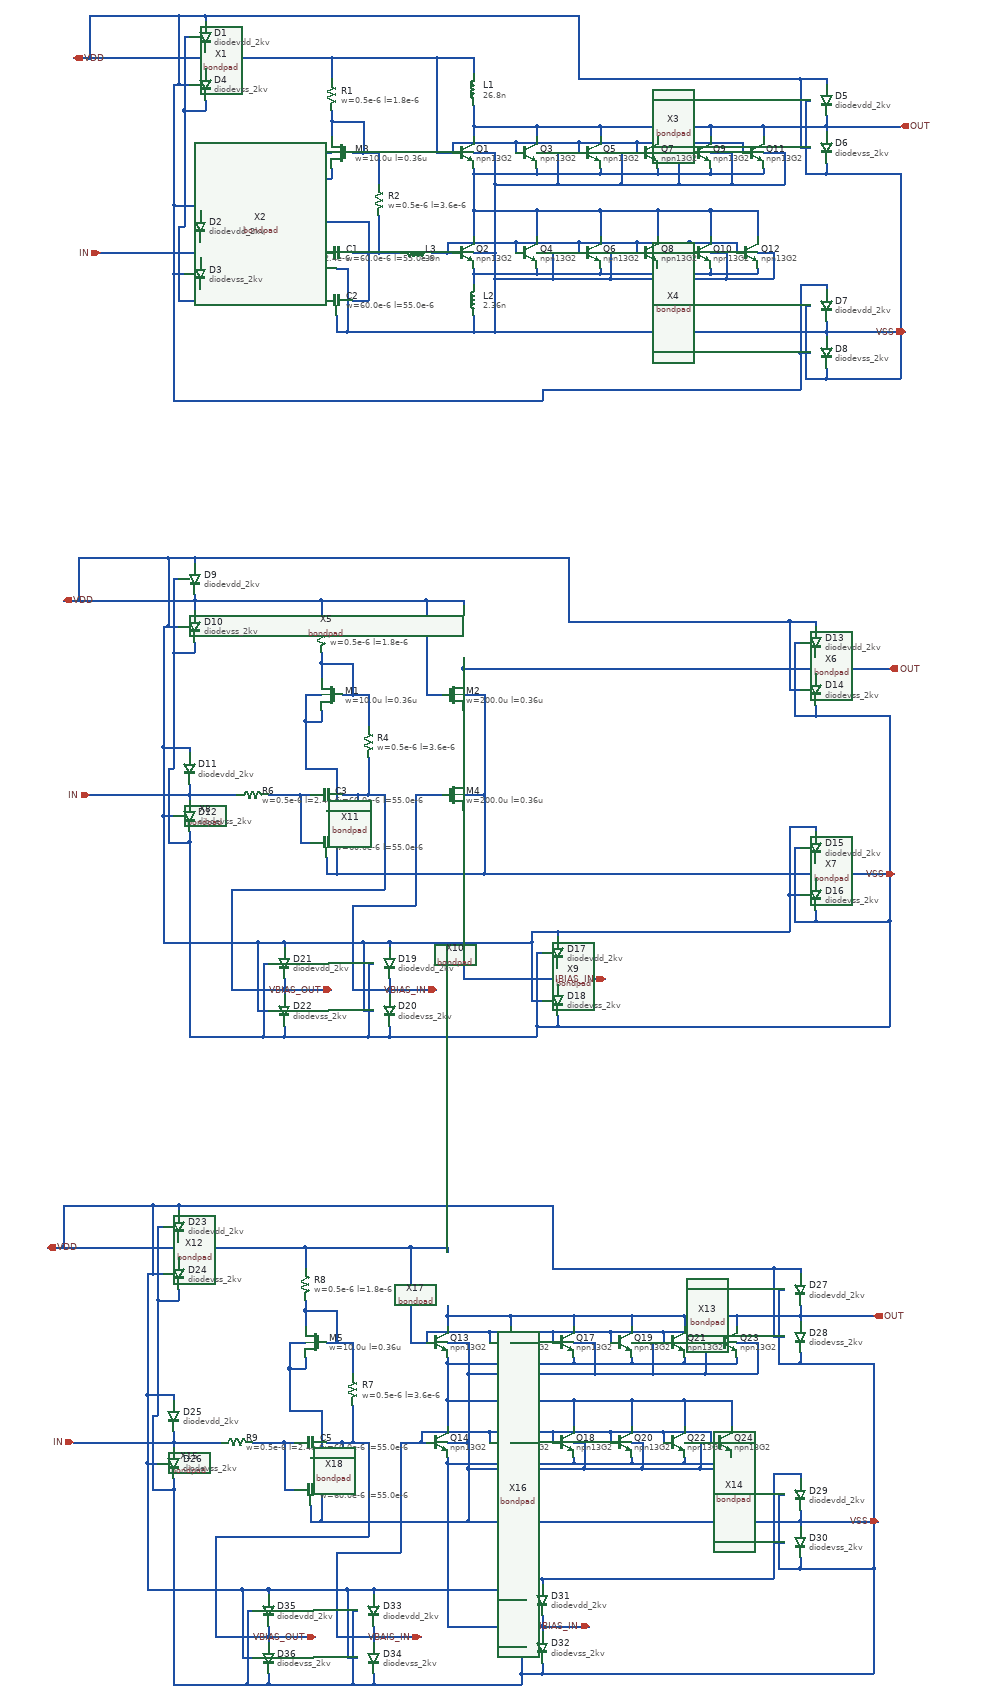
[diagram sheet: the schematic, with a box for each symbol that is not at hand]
v {xschem version=3.4.6 file_version=1.2}
G {}
K {}
V {}
S {}
E {}
N 0 -250 0 -220 {lab=#net1}
N 270 -240 270 -220 {lab=OUT}
N 270 -80 270 -30 {lab=#net2}
N 220 -0 230 0 {lab=#net3}
N -40 0 -20 0 {lab=#net4}
N 90 -70 90 0 {lab=#net5}
N 70 0 90 0 {lab=#net5}
N 70 0 70 90 {lab=#net5}
N 40 0 70 0 {lab=#net5}
N 40 90 70 90 {lab=#net5}
N -40 90 -20 90 {lab=#net4}
N -40 0 -40 90 {lab=#net4}
N -100 0 -40 0 {lab=#net4}
N 60 -190 90 -190 {lab=#net1}
N 90 -190 90 -130 {lab=#net1}
N 0 -250 60 -250 {lab=#net1}
N 0 -270 0 -250 {lab=#net1}
N 60 -250 60 -190 {lab=#net1}
N 40 -190 60 -190 {lab=#net1}
N 270 0 310 0 {lab=VSS}
N 270 -190 310 -190 {lab=VSS}
N 0 -370 0 -330 {lab=VDD}
N 310 50 310 150 {lab=VSS}
N -30 -190 0 -190 {lab=#net5}
N -30 -190 -30 -140 {lab=#net5}
N -30 -140 0 -140 {lab=#net5}
N 0 -160 0 -140 {lab=#net5}
N 200 -190 230 -190 {lab=VDD}
N 200 -370 200 -190 {lab=VDD}
N 10 30 30 30 {lab=VSS}
N 30 30 30 150 {lab=VSS}
N 10 120 10 150 {lab=VSS}
N 10 150 30 150 {lab=VSS}
N -240 -370 -240 -350 {lab=VDD}
N -240 -370 0 -370 {lab=VDD}
N -240 -380 -240 -370 {lab=VDD}
N -440 0 -250 -0 {lab=IN}
N 270 -80 390 -80 {lab=#net2}
N 390 -80 390 -30 {lab=#net2}
N 390 0 420 -0 {lab=VSS}
N 350 -20 350 -0 {lab=#net3}
N 220 -20 350 -20 {lab=#net3}
N 220 -20 220 -0 {lab=#net3}
N 0 -370 200 -370 {lab=VDD}
N 270 -150 270 -80 {lab=#net2}
N 310 -130 310 0 {lab=VSS}
N 470 -20 470 0 {lab=#net3}
N 350 -20 470 -20 {lab=#net3}
N 390 -80 510 -80 {lab=#net2}
N 510 -80 510 -30 {lab=#net2}
N 510 30 510 40 {lab=#net6}
N 510 0 530 0 {lab=VSS}
N 530 0 530 50 {lab=VSS}
N 390 30 390 40 {lab=#net6}
N 270 40 390 40 {lab=#net6}
N 270 30 270 40 {lab=#net6}
N 390 40 510 40 {lab=#net6}
N 420 50 530 50 {lab=VSS}
N 420 -0 420 50 {lab=VSS}
N 230 -210 230 -190 {lab=VDD}
N 230 -210 350 -210 {lab=VDD}
N 350 -210 350 -190 {lab=VDD}
N 350 -210 470 -210 {lab=VDD}
N 470 -210 470 -190 {lab=VDD}
N 270 -150 390 -150 {lab=#net2}
N 270 -160 270 -150 {lab=#net2}
N 390 -160 390 -150 {lab=#net2}
N 390 -150 510 -150 {lab=#net2}
N 510 -160 510 -150 {lab=#net2}
N 390 -240 390 -220 {lab=OUT}
N 270 -240 390 -240 {lab=OUT}
N 510 -240 510 -220 {lab=OUT}
N 390 -240 510 -240 {lab=OUT}
N 390 -190 430 -190 {lab=VSS}
N 430 -190 430 -130 {lab=VSS}
N 310 -130 430 -130 {lab=VSS}
N 310 -190 310 -130 {lab=VSS}
N 510 -190 550 -190 {lab=VSS}
N 550 -190 550 -130 {lab=VSS}
N 430 -130 550 -130 {lab=VSS}
N 310 50 420 50 {lab=VSS}
N 310 0 310 50 {lab=VSS}
N 620 -240 620 -220 {lab=OUT}
N 510 -240 620 -240 {lab=OUT}
N 580 -210 580 -190 {lab=VDD}
N 470 -210 580 -210 {lab=VDD}
N 620 -160 620 -150 {lab=#net2}
N 510 -150 620 -150 {lab=#net2}
N 620 -190 660 -190 {lab=VSS}
N 660 -190 660 -130 {lab=VSS}
N 550 -130 660 -130 {lab=VSS}
N 620 -80 620 -30 {lab=#net2}
N 510 -80 620 -80 {lab=#net2}
N 580 -20 580 -0 {lab=#net3}
N 470 -20 580 -20 {lab=#net3}
N 620 30 620 40 {lab=#net6}
N 510 40 620 40 {lab=#net6}
N 620 -0 640 0 {lab=VSS}
N 640 0 640 50 {lab=VSS}
N 530 50 640 50 {lab=VSS}
N -240 -450 -240 -440 {lab=VDD}
N -290 -320 -270 -320 {lab=VDD}
N -290 -450 -290 -320 {lab=VDD}
N -290 -450 -240 -450 {lab=VDD}
N -280 -410 -270 -410 {lab=#net7}
N -280 -410 -280 -270 {lab=#net7}
N -280 -270 -240 -270 {lab=#net7}
N -240 -290 -240 -270 {lab=#net7}
N -250 -0 -250 10 {lab=IN}
N -250 -90 -250 -80 {lab=VDD}
N -300 40 -280 40 {lab=VDD}
N -300 -90 -300 40 {lab=VDD}
N -300 -90 -250 -90 {lab=VDD}
N -290 -50 -280 -50 {lab=#net7}
N -290 -50 -290 90 {lab=#net7}
N -290 90 -250 90 {lab=#net7}
N -250 70 -250 90 {lab=#net7}
N 940 -240 940 -230 {lab=OUT}
N 940 -330 940 -320 {lab=VDD}
N 890 -200 910 -200 {lab=VDD}
N 890 -330 890 -200 {lab=VDD}
N 890 -330 940 -330 {lab=VDD}
N 900 -290 910 -290 {lab=VSS}
N 900 -290 900 -150 {lab=VSS}
N 900 -150 940 -150 {lab=VSS}
N 940 -170 940 -150 {lab=VSS}
N 940 150 940 160 {lab=VSS}
N 940 60 940 70 {lab=VDD}
N 890 190 910 190 {lab=VDD}
N 890 60 890 190 {lab=VDD}
N 890 60 940 60 {lab=VDD}
N 900 100 910 100 {lab=VSS}
N 900 100 900 240 {lab=VSS}
N 900 240 940 240 {lab=VSS}
N 940 220 940 240 {lab=VSS}
N 940 130 940 150 {lab=VSS}
N 310 150 940 150 {lab=VSS}
N 940 -260 940 -240 {lab=OUT}
N 820 -240 940 -240 {lab=OUT}
N -250 -20 -250 -0 {lab=IN}
N -250 -0 -160 0 {lab=IN}
N -460 -370 -240 -370 {lab=VDD}
N 720 -240 720 -220 {lab=OUT}
N 620 -240 720 -240 {lab=OUT}
N 720 -160 720 -150 {lab=#net2}
N 620 -150 720 -150 {lab=#net2}
N 680 -210 680 -190 {lab=VDD}
N 580 -210 680 -210 {lab=VDD}
N 720 -190 760 -190 {lab=VSS}
N 760 -190 760 -130 {lab=VSS}
N 660 -130 760 -130 {lab=VSS}
N 680 -20 680 -0 {lab=#net3}
N 580 -20 680 -20 {lab=#net3}
N 720 -80 720 -30 {lab=#net2}
N 620 -80 720 -80 {lab=#net2}
N 720 0 750 0 {lab=VSS}
N 750 0 750 50 {lab=VSS}
N 640 50 750 50 {lab=VSS}
N 720 30 720 40 {lab=#net6}
N 620 40 720 40 {lab=#net6}
N 720 -80 810 -80 {lab=#net2}
N 810 -80 810 -30 {lab=#net2}
N 770 -20 770 -0 {lab=#net3}
N 680 -20 770 -20 {lab=#net3}
N 810 0 840 0 {lab=VSS}
N 840 0 840 50 {lab=VSS}
N 750 50 840 50 {lab=VSS}
N 810 30 810 40 {lab=#net6}
N 720 40 810 40 {lab=#net6}
N 780 -210 780 -190 {lab=VDD}
N 680 -210 780 -210 {lab=VDD}
N 820 -240 820 -220 {lab=OUT}
N 720 -240 820 -240 {lab=OUT}
N 820 -190 860 -190 {lab=VSS}
N 860 -190 860 -130 {lab=VSS}
N 760 -130 860 -130 {lab=VSS}
N 820 -160 820 -150 {lab=#net2}
N 720 -150 820 -150 {lab=#net2}
N 200 -370 270 -370 {lab=VDD}
N 400 260 890 260 {lab=VDD}
N 1080 150 1090 150 {lab=VSS}
N 940 -240 1080 -240 {lab=OUT}
N -280 -270 -280 -50 {lab=#net7}
N 940 150 1080 150 {lab=VSS}
N 1080 -150 1080 150 {lab=VSS}
N 940 -150 1080 -150 {lab=VSS}
N -460 -450 -290 -450 {lab=VDD}
N -460 -450 -460 -370 {lab=VDD}
N -490 -370 -460 -370 {lab=VDD}
N -300 -320 -300 -90 {lab=VDD}
N -300 -320 -290 -320 {lab=VDD}
N -300 280 400 280 {lab=VDD}
N -300 40 -300 280 {lab=VDD}
N 400 260 400 280 {lab=VDD}
N 940 240 1080 240 {lab=VSS}
N 1080 150 1080 240 {lab=VSS}
N -240 -450 470 -450 {lab=VDD}
N 470 -450 470 -330 {lab=VDD}
N 470 -330 890 -330 {lab=VDD}
N 890 190 890 260 {lab=VDD}
N 270 150 310 150 {lab=VSS}
N 270 -370 270 -340 {lab=VDD}
N 270 -280 270 -240 {lab=OUT}
N 270 40 270 60 {lab=#net6}
N 270 120 270 150 {lab=VSS}
N 30 150 270 150 {lab=VSS}
N 90 0 130 0 {lab=#net5}
N 190 -0 220 -0 {lab=#net3}
N -30 -140 -30 -60 {lab=#net5}
N -30 -60 70 -60 {lab=#net5}
N 70 -60 70 0 {lab=#net5}
N -20 780 -20 810 {lab=#net1}
N 250 790 250 810 {lab=OUT}
N -60 1030 -40 1030 {lab=#net2}
N 70 960 70 1030 {lab=VBIAS_OUT}
N 50 1030 70 1030 {lab=VBIAS_OUT}
N 50 1030 50 1120 {lab=VBIAS_OUT}
N 20 1030 50 1030 {lab=VBIAS_OUT}
N 20 1120 50 1120 {lab=VBIAS_OUT}
N -60 1120 -40 1120 {lab=#net2}
N -60 1030 -60 1120 {lab=#net2}
N -120 1030 -60 1030 {lab=#net2}
N 40 840 70 840 {lab=#net1}
N 70 840 70 900 {lab=#net1}
N -20 780 40 780 {lab=#net1}
N -20 760 -20 780 {lab=#net1}
N 40 780 40 840 {lab=#net1}
N 20 840 40 840 {lab=#net1}
N 250 1030 290 1030 {lab=VSS}
N 250 840 290 840 {lab=VSS}
N -20 660 -20 700 {lab=VDD}
N -50 840 -20 840 {lab=VSS}
N -50 840 -50 890 {lab=VSS}
N -50 890 -20 890 {lab=VSS}
N -20 870 -20 890 {lab=VSS}
N 250 770 250 790 {lab=OUT}
N 180 840 210 840 {lab=VDD}
N 180 660 180 840 {lab=VDD}
N -10 1060 10 1060 {lab=VSS}
N 10 1060 10 1180 {lab=VSS}
N 10 1180 290 1180 {lab=VSS}
N -10 1150 -10 1180 {lab=VSS}
N -10 1180 10 1180 {lab=VSS}
N -260 660 -260 680 {lab=VDD}
N -260 660 -20 660 {lab=VDD}
N -260 650 -260 660 {lab=VDD}
N -460 1030 -270 1030 {lab=IN}
N -20 660 180 660 {lab=VDD}
N 250 1060 250 1380 {lab=IBIAS_IN}
N 250 870 250 1000 {lab=#net3}
N 250 790 920 790 {lab=OUT}
N 290 840 290 1030 {lab=VSS}
N 290 1030 290 1180 {lab=VSS}
N -260 580 -260 590 {lab=VDD}
N -310 710 -290 710 {lab=VDD}
N -310 580 -310 710 {lab=VDD}
N -310 580 -260 580 {lab=VDD}
N -300 620 -290 620 {lab=VSS}
N -300 620 -300 760 {lab=VSS}
N -300 760 -260 760 {lab=VSS}
N -260 740 -260 760 {lab=VSS}
N -270 1030 -270 1040 {lab=IN}
N -270 940 -270 950 {lab=VDD}
N -320 1070 -300 1070 {lab=VDD}
N -320 940 -320 1070 {lab=VDD}
N -320 940 -270 940 {lab=VDD}
N -270 1120 -270 1490 {lab=VSS}
N -310 980 -300 980 {lab=VSS}
N -310 980 -310 1120 {lab=VSS}
N -310 1120 -270 1120 {lab=VSS}
N -270 1100 -270 1120 {lab=VSS}
N 920 790 920 800 {lab=OUT}
N 920 700 920 710 {lab=VDD}
N 870 830 890 830 {lab=VDD}
N 870 700 870 830 {lab=VDD}
N 870 700 920 700 {lab=VDD}
N 880 740 890 740 {lab=VSS}
N 880 740 880 880 {lab=VSS}
N 880 880 920 880 {lab=VSS}
N 920 860 920 880 {lab=VSS}
N 920 1180 920 1190 {lab=VSS}
N 920 1090 920 1100 {lab=VDD}
N 870 1220 890 1220 {lab=VDD}
N 870 1090 870 1220 {lab=VDD}
N 870 1090 920 1090 {lab=VDD}
N 880 1130 890 1130 {lab=VSS}
N 880 1130 880 1270 {lab=VSS}
N 880 1270 920 1270 {lab=VSS}
N 920 1250 920 1270 {lab=VSS}
N 920 1160 920 1180 {lab=VSS}
N 290 1180 920 1180 {lab=VSS}
N 920 770 920 790 {lab=OUT}
N -270 1010 -270 1030 {lab=IN}
N -270 1030 -180 1030 {lab=IN}
N -480 660 -260 660 {lab=VDD}
N 180 660 250 660 {lab=VDD}
N 250 660 250 670 {lab=VDD}
N 430 1290 430 1300 {lab=VDD}
N 380 1420 400 1420 {lab=VDD}
N 380 1310 380 1420 {lab=VDD}
N 380 1290 430 1290 {lab=VDD}
N 390 1330 400 1330 {lab=VSS}
N 390 1330 390 1470 {lab=VSS}
N 390 1470 430 1470 {lab=VSS}
N 430 1450 430 1470 {lab=VSS}
N 430 1380 430 1390 {lab=IBIAS_IN}
N 430 1360 430 1380 {lab=IBIAS_IN}
N 250 1380 430 1380 {lab=IBIAS_IN}
N 110 1310 110 1320 {lab=VDD}
N 60 1440 80 1440 {lab=VDD}
N 60 1310 60 1440 {lab=VDD}
N 60 1310 110 1310 {lab=VDD}
N 70 1350 80 1350 {lab=VSS}
N 70 1350 70 1490 {lab=VSS}
N 70 1490 110 1490 {lab=VSS}
N 110 1470 110 1490 {lab=VSS}
N 110 1400 110 1410 {lab=VBIAS_IN}
N 70 1030 100 1030 {lab=VBIAS_OUT}
N 160 1030 210 1030 {lab=VBIAS_IN}
N -90 1310 -90 1320 {lab=VDD}
N -140 1440 -120 1440 {lab=VDD}
N -140 1310 -140 1440 {lab=VDD}
N -140 1310 -90 1310 {lab=VDD}
N -130 1350 -120 1350 {lab=VSS}
N -130 1350 -130 1490 {lab=VSS}
N -130 1490 -90 1490 {lab=VSS}
N -90 1470 -90 1490 {lab=VSS}
N -90 1400 -90 1410 {lab=VBIAS_OUT}
N 100 1030 100 1210 {lab=VBIAS_OUT}
N -190 1210 100 1210 {lab=VBIAS_OUT}
N -190 1210 -190 1400 {lab=VBIAS_OUT}
N -190 1400 -90 1400 {lab=VBIAS_OUT}
N -90 1380 -90 1400 {lab=VBIAS_OUT}
N -90 1400 0 1400 {lab=VBIAS_OUT}
N 160 1030 160 1240 {lab=VBIAS_IN}
N 40 1240 160 1240 {lab=VBIAS_IN}
N 40 1240 40 1400 {lab=VBIAS_IN}
N 40 1400 110 1400 {lab=VBIAS_IN}
N 110 1380 110 1400 {lab=VBIAS_IN}
N 110 1400 200 1400 {lab=VBIAS_IN}
N 1060 1180 1070 1180 {lab=VSS}
N 920 790 1060 790 {lab=OUT}
N -90 1490 70 1490 {lab=VSS}
N 110 1490 390 1490 {lab=VSS}
N 390 1470 390 1490 {lab=VSS}
N 430 1470 1060 1470 {lab=VSS}
N -270 1490 -130 1490 {lab=VSS}
N -300 760 -300 980 {lab=VSS}
N 430 1380 520 1380 {lab=IBIAS_IN}
N 1060 1270 1060 1470 {lab=VSS}
N 920 1180 1060 1180 {lab=VSS}
N 1060 880 1060 1180 {lab=VSS}
N 920 880 1060 880 {lab=VSS}
N -480 580 -310 580 {lab=VDD}
N -480 580 -480 660 {lab=VDD}
N -510 660 -480 660 {lab=VDD}
N -320 710 -320 940 {lab=VDD}
N -320 710 -310 710 {lab=VDD}
N -320 1310 -140 1310 {lab=VDD}
N -320 1070 -320 1310 {lab=VDD}
N -90 1310 60 1310 {lab=VDD}
N 110 1310 380 1310 {lab=VDD}
N 380 1290 380 1310 {lab=VDD}
N 920 1270 1060 1270 {lab=VSS}
N 1060 1180 1060 1270 {lab=VSS}
N -260 580 450 580 {lab=VDD}
N 450 580 450 700 {lab=VDD}
N 450 700 870 700 {lab=VDD}
N 430 1290 870 1290 {lab=VDD}
N 870 1220 870 1290 {lab=VDD}
N -50 890 -50 980 {lab=VSS}
N -50 980 10 980 {lab=VSS}
N 10 980 10 1060 {lab=VSS}
N -50 2010 -50 2040 {lab=#net1}
N 220 2020 220 2040 {lab=OUT}
N 220 2180 220 2230 {lab=#net2}
N 220 2300 220 2610 {lab=IBIAS_IN}
N 170 2260 180 2260 {lab=VBAIS_IN}
N -90 2260 -70 2260 {lab=#net3}
N 40 2190 40 2260 {lab=VBIAS_OUT}
N 20 2260 40 2260 {lab=VBIAS_OUT}
N 20 2260 20 2350 {lab=VBIAS_OUT}
N -10 2260 20 2260 {lab=VBIAS_OUT}
N -10 2350 20 2350 {lab=VBIAS_OUT}
N -90 2350 -70 2350 {lab=#net3}
N -90 2260 -90 2350 {lab=#net3}
N -150 2260 -90 2260 {lab=#net3}
N 10 2070 40 2070 {lab=#net1}
N 40 2070 40 2130 {lab=#net1}
N -50 2010 10 2010 {lab=#net1}
N -50 1990 -50 2010 {lab=#net1}
N 10 2010 10 2070 {lab=#net1}
N -10 2070 10 2070 {lab=#net1}
N 220 2260 260 2260 {lab=VSS}
N 220 2070 260 2070 {lab=VSS}
N -50 1890 -50 1930 {lab=VDD}
N 260 2310 260 2410 {lab=VSS}
N -80 2070 -50 2070 {lab=VSS}
N -80 2070 -80 2120 {lab=VSS}
N -80 2120 -50 2120 {lab=VSS}
N -50 2100 -50 2120 {lab=VSS}
N 220 2000 220 2020 {lab=OUT}
N 150 2070 180 2070 {lab=VDD}
N 150 1890 150 2070 {lab=VDD}
N -40 2290 -20 2290 {lab=VSS}
N -20 2290 -20 2410 {lab=VSS}
N -20 2410 260 2410 {lab=VSS}
N -40 2380 -40 2410 {lab=VSS}
N -40 2410 -20 2410 {lab=VSS}
N -290 1890 -290 1910 {lab=VDD}
N -290 1890 -50 1890 {lab=VDD}
N -290 1880 -290 1890 {lab=VDD}
N -490 2260 -300 2260 {lab=IN}
N 220 2180 340 2180 {lab=#net2}
N 340 2180 340 2230 {lab=#net2}
N 340 2260 370 2260 {lab=VSS}
N 300 2240 300 2260 {lab=VBAIS_IN}
N 170 2240 300 2240 {lab=VBAIS_IN}
N 170 2240 170 2260 {lab=VBAIS_IN}
N -50 1890 150 1890 {lab=VDD}
N 220 2110 220 2180 {lab=#net2}
N 260 2130 260 2260 {lab=VSS}
N 420 2240 420 2260 {lab=VBAIS_IN}
N 300 2240 420 2240 {lab=VBAIS_IN}
N 340 2180 460 2180 {lab=#net2}
N 460 2180 460 2230 {lab=#net2}
N 460 2290 460 2300 {lab=IBIAS_IN}
N 460 2260 480 2260 {lab=VSS}
N 480 2260 480 2310 {lab=VSS}
N 340 2290 340 2300 {lab=IBIAS_IN}
N 220 2300 340 2300 {lab=IBIAS_IN}
N 220 2290 220 2300 {lab=IBIAS_IN}
N 340 2300 460 2300 {lab=IBIAS_IN}
N 370 2310 480 2310 {lab=VSS}
N 370 2260 370 2310 {lab=VSS}
N 180 2050 180 2070 {lab=VDD}
N 180 2050 300 2050 {lab=VDD}
N 300 2050 300 2070 {lab=VDD}
N 300 2050 420 2050 {lab=VDD}
N 420 2050 420 2070 {lab=VDD}
N 220 2110 340 2110 {lab=#net2}
N 220 2100 220 2110 {lab=#net2}
N 340 2100 340 2110 {lab=#net2}
N 340 2110 460 2110 {lab=#net2}
N 460 2100 460 2110 {lab=#net2}
N 340 2020 340 2040 {lab=OUT}
N 220 2020 340 2020 {lab=OUT}
N 460 2020 460 2040 {lab=OUT}
N 340 2020 460 2020 {lab=OUT}
N 340 2070 380 2070 {lab=VSS}
N 380 2070 380 2130 {lab=VSS}
N 260 2130 380 2130 {lab=VSS}
N 260 2070 260 2130 {lab=VSS}
N 460 2070 500 2070 {lab=VSS}
N 500 2070 500 2130 {lab=VSS}
N 380 2130 500 2130 {lab=VSS}
N 260 2310 370 2310 {lab=VSS}
N 260 2260 260 2310 {lab=VSS}
N 570 2020 570 2040 {lab=OUT}
N 460 2020 570 2020 {lab=OUT}
N 530 2050 530 2070 {lab=VDD}
N 420 2050 530 2050 {lab=VDD}
N 570 2100 570 2110 {lab=#net2}
N 460 2110 570 2110 {lab=#net2}
N 570 2070 610 2070 {lab=VSS}
N 610 2070 610 2130 {lab=VSS}
N 500 2130 610 2130 {lab=VSS}
N 570 2180 570 2230 {lab=#net2}
N 460 2180 570 2180 {lab=#net2}
N 530 2240 530 2260 {lab=VBAIS_IN}
N 420 2240 530 2240 {lab=VBAIS_IN}
N 570 2290 570 2300 {lab=IBIAS_IN}
N 460 2300 570 2300 {lab=IBIAS_IN}
N 570 2260 590 2260 {lab=VSS}
N 590 2260 590 2310 {lab=VSS}
N 480 2310 590 2310 {lab=VSS}
N -290 1810 -290 1820 {lab=VDD}
N -340 1940 -320 1940 {lab=VDD}
N -340 1810 -340 1940 {lab=VDD}
N -340 1810 -290 1810 {lab=VDD}
N -330 1850 -320 1850 {lab=VSS}
N -330 1850 -330 1990 {lab=VSS}
N -330 1990 -290 1990 {lab=VSS}
N -290 1970 -290 1990 {lab=VSS}
N -300 2260 -300 2270 {lab=IN}
N -300 2170 -300 2180 {lab=VDD}
N -350 2300 -330 2300 {lab=VDD}
N -350 2170 -350 2300 {lab=VDD}
N -350 2170 -300 2170 {lab=VDD}
N -300 2350 -300 2720 {lab=VSS}
N -340 2210 -330 2210 {lab=VSS}
N -340 2210 -340 2350 {lab=VSS}
N -340 2350 -300 2350 {lab=VSS}
N -300 2330 -300 2350 {lab=VSS}
N 890 2020 890 2030 {lab=OUT}
N 890 1930 890 1940 {lab=VDD}
N 840 2060 860 2060 {lab=VDD}
N 840 1930 840 2060 {lab=VDD}
N 840 1930 890 1930 {lab=VDD}
N 850 1970 860 1970 {lab=VSS}
N 850 1970 850 2110 {lab=VSS}
N 850 2110 890 2110 {lab=VSS}
N 890 2090 890 2110 {lab=VSS}
N 890 2410 890 2420 {lab=VSS}
N 890 2320 890 2330 {lab=VDD}
N 840 2450 860 2450 {lab=VDD}
N 840 2320 840 2450 {lab=VDD}
N 840 2320 890 2320 {lab=VDD}
N 850 2360 860 2360 {lab=VSS}
N 850 2360 850 2500 {lab=VSS}
N 850 2500 890 2500 {lab=VSS}
N 890 2480 890 2500 {lab=VSS}
N 890 2390 890 2410 {lab=VSS}
N 260 2410 890 2410 {lab=VSS}
N 890 2000 890 2020 {lab=OUT}
N 770 2020 890 2020 {lab=OUT}
N -300 2240 -300 2260 {lab=IN}
N -300 2260 -210 2260 {lab=IN}
N -510 1890 -290 1890 {lab=VDD}
N 670 2020 670 2040 {lab=OUT}
N 570 2020 670 2020 {lab=OUT}
N 670 2100 670 2110 {lab=#net2}
N 570 2110 670 2110 {lab=#net2}
N 630 2050 630 2070 {lab=VDD}
N 530 2050 630 2050 {lab=VDD}
N 670 2070 710 2070 {lab=VSS}
N 710 2070 710 2130 {lab=VSS}
N 610 2130 710 2130 {lab=VSS}
N 630 2240 630 2260 {lab=VBAIS_IN}
N 530 2240 630 2240 {lab=VBAIS_IN}
N 670 2180 670 2230 {lab=#net2}
N 570 2180 670 2180 {lab=#net2}
N 670 2260 700 2260 {lab=VSS}
N 700 2260 700 2310 {lab=VSS}
N 590 2310 700 2310 {lab=VSS}
N 670 2290 670 2300 {lab=IBIAS_IN}
N 570 2300 670 2300 {lab=IBIAS_IN}
N 670 2180 760 2180 {lab=#net2}
N 760 2180 760 2230 {lab=#net2}
N 720 2240 720 2260 {lab=VBAIS_IN}
N 630 2240 720 2240 {lab=VBAIS_IN}
N 760 2260 790 2260 {lab=VSS}
N 790 2260 790 2310 {lab=VSS}
N 700 2310 790 2310 {lab=VSS}
N 760 2290 760 2300 {lab=IBIAS_IN}
N 670 2300 760 2300 {lab=IBIAS_IN}
N 730 2050 730 2070 {lab=VDD}
N 630 2050 730 2050 {lab=VDD}
N 770 2020 770 2040 {lab=OUT}
N 670 2020 770 2020 {lab=OUT}
N 770 2070 810 2070 {lab=VSS}
N 810 2070 810 2130 {lab=VSS}
N 710 2130 810 2130 {lab=VSS}
N 770 2100 770 2110 {lab=#net2}
N 670 2110 770 2110 {lab=#net2}
N 150 1890 220 1890 {lab=VDD}
N 220 1890 220 1900 {lab=VDD}
N 400 2520 400 2530 {lab=VDD}
N 350 2650 370 2650 {lab=VDD}
N 350 2540 350 2650 {lab=VDD}
N 350 2520 400 2520 {lab=VDD}
N 360 2560 370 2560 {lab=VSS}
N 360 2560 360 2700 {lab=VSS}
N 360 2700 400 2700 {lab=VSS}
N 400 2680 400 2700 {lab=VSS}
N 400 2610 400 2620 {lab=IBIAS_IN}
N 400 2590 400 2610 {lab=IBIAS_IN}
N 220 2610 400 2610 {lab=IBIAS_IN}
N 80 2540 80 2550 {lab=VDD}
N 30 2670 50 2670 {lab=VDD}
N 30 2540 30 2670 {lab=VDD}
N 30 2540 80 2540 {lab=VDD}
N 40 2580 50 2580 {lab=VSS}
N 40 2580 40 2720 {lab=VSS}
N 40 2720 80 2720 {lab=VSS}
N 80 2700 80 2720 {lab=VSS}
N 80 2630 80 2640 {lab=VBAIS_IN}
N 40 2260 70 2260 {lab=VBIAS_OUT}
N 130 2260 170 2260 {lab=VBAIS_IN}
N -120 2540 -120 2550 {lab=VDD}
N -170 2670 -150 2670 {lab=VDD}
N -170 2540 -170 2670 {lab=VDD}
N -170 2540 -120 2540 {lab=VDD}
N -160 2580 -150 2580 {lab=VSS}
N -160 2580 -160 2720 {lab=VSS}
N -160 2720 -120 2720 {lab=VSS}
N -120 2700 -120 2720 {lab=VSS}
N -120 2630 -120 2640 {lab=VBIAS_OUT}
N 70 2260 70 2440 {lab=VBIAS_OUT}
N -220 2440 70 2440 {lab=VBIAS_OUT}
N -220 2440 -220 2630 {lab=VBIAS_OUT}
N -220 2630 -120 2630 {lab=VBIAS_OUT}
N -120 2610 -120 2630 {lab=VBIAS_OUT}
N -120 2630 -30 2630 {lab=VBIAS_OUT}
N 130 2260 130 2470 {lab=VBAIS_IN}
N 10 2470 130 2470 {lab=VBAIS_IN}
N 10 2470 10 2630 {lab=VBAIS_IN}
N 10 2630 80 2630 {lab=VBAIS_IN}
N 80 2610 80 2630 {lab=VBAIS_IN}
N 80 2630 170 2630 {lab=VBAIS_IN}
N 1030 2410 1040 2410 {lab=VSS}
N 890 2020 1030 2020 {lab=OUT}
N -120 2720 40 2720 {lab=VSS}
N 80 2720 360 2720 {lab=VSS}
N 360 2700 360 2720 {lab=VSS}
N 400 2700 1030 2700 {lab=VSS}
N -300 2720 -160 2720 {lab=VSS}
N -330 1990 -330 2210 {lab=VSS}
N 400 2610 490 2610 {lab=IBIAS_IN}
N 1030 2500 1030 2700 {lab=VSS}
N 890 2410 1030 2410 {lab=VSS}
N 1030 2110 1030 2410 {lab=VSS}
N 890 2110 1030 2110 {lab=VSS}
N -510 1810 -340 1810 {lab=VDD}
N -510 1810 -510 1890 {lab=VDD}
N -540 1890 -510 1890 {lab=VDD}
N -350 1940 -350 2170 {lab=VDD}
N -350 1940 -340 1940 {lab=VDD}
N -350 2540 -170 2540 {lab=VDD}
N -350 2300 -350 2540 {lab=VDD}
N -120 2540 30 2540 {lab=VDD}
N 80 2540 350 2540 {lab=VDD}
N 350 2520 350 2540 {lab=VDD}
N 890 2500 1030 2500 {lab=VSS}
N 1030 2410 1030 2500 {lab=VSS}
N -290 1810 420 1810 {lab=VDD}
N 420 1810 420 1930 {lab=VDD}
N 420 1930 840 1930 {lab=VDD}
N 400 2520 840 2520 {lab=VDD}
N 840 2450 840 2520 {lab=VDD}
N -80 2120 -80 2200 {lab=VSS}
N -80 2200 -20 2200 {lab=VSS}
N -20 2200 -20 2290 {lab=VSS}
C {sg13g2_pr/rppd.sym} 90 -100 0 0 {name=R2
w=0.5e-6
l=3.6e-6
model=rppd
spiceprefix=X
b=0
m=1
}
C {sg13g2_pr/rppd.sym} 0 -300 0 0 {name=R1
w=0.5e-6
l=1.8e-6
model=rppd
spiceprefix=X
b=0
m=1
}
C {sg13g2_pr/rsil.sym} -130 0 3 0 {name=R3
w=0.5e-6
l=2.4e-6
model=rsil
spiceprefix=X
b=0
m=1
}
C {sg13g2_pr/cap_rfcmim.sym} 10 0 3 0 {name=C1 
model=rfcmim
w=60.0e-6
l=55.0e-6
wfeed=5.0e-6
spiceprefix=X}
C {sg13g2_pr/cap_rfcmim.sym} 10 90 3 0 {name=C2 
model=rfcmim
w=60.0e-6
l=55.0e-6
wfeed=5.0e-6
spiceprefix=X}
C {sg13g2_pr/sg13_lv_rf_nmos.sym} 20 -190 2 0 {name=M3
l=0.36u
w=10.0u
ng=5
m=1
rfmode=1
model=rfnmos
spiceprefix=X
}
C {sg13g2_pr/bondpad.sym} -400 -410 0 0 {name=X1
model=bondpad
spiceprefix=X
size=100u
shape=0
padtype=0
}
C {sg13g2_pr/bondpad.sym} 1030 -280 0 0 {name=X3
model=bondpad
spiceprefix=X
size=100u
shape=0
padtype=0
}
C {sg13g2_pr/bondpad.sym} 1040 110 0 0 {name=X4
model=bondpad
spiceprefix=X
size=100u
shape=0
padtype=0
}
C {sg13g2_pr/diodevdd_2kv.sym} -240 -410 0 0 {name=D1
model=diodevdd_2kv
m=1
spiceprefix=X
}
C {sg13g2_pr/diodevss_2kv.sym} -240 -320 0 0 {name=D4
model=diodevss_2kv
spiceprefix=X
m=1
}
C {sg13g2_pr/bondpad.sym} -380 -40 0 0 {name=X2
model=bondpad
spiceprefix=X
size=100u
shape=0
padtype=0
}
C {sg13g2_pr/npn13G2.sym} 250 -190 0 0 {name=Q1
model=npn13G2
spiceprefix=X
Nx=10
m=10}
C {sg13g2_pr/npn13G2.sym} 250 0 0 0 {name=Q2
model=npn13G2
spiceprefix=X
Nx=10
m=10}
C {sg13g2_pr/npn13G2.sym} 370 -190 0 0 {name=Q3
model=npn13G2
spiceprefix=X
Nx=10}
C {sg13g2_pr/npn13G2.sym} 370 0 0 0 {name=Q4
model=npn13G2
spiceprefix=X
Nx=10}
C {sg13g2_pr/npn13G2.sym} 490 -190 0 0 {name=Q5
model=npn13G2
spiceprefix=X
Nx=10}
C {sg13g2_pr/npn13G2.sym} 490 0 0 0 {name=Q6
model=npn13G2
spiceprefix=X
Nx=10}
C {sg13g2_pr/npn13G2.sym} 600 -190 0 0 {name=Q7
model=npn13G2
spiceprefix=X
Nx=10}
C {sg13g2_pr/npn13G2.sym} 600 0 0 0 {name=Q8
model=npn13G2
spiceprefix=X
Nx=10}
C {sg13g2_pr/diodevdd_2kv.sym} -250 -50 0 0 {name=D2
model=diodevdd_2kv
m=1
spiceprefix=X
}
C {sg13g2_pr/diodevss_2kv.sym} -250 40 0 0 {name=D3
model=diodevss_2kv
spiceprefix=X
m=1
}
C {sg13g2_pr/diodevdd_2kv.sym} 940 -290 0 0 {name=D5
model=diodevdd_2kv
m=1
spiceprefix=X
}
C {sg13g2_pr/diodevss_2kv.sym} 940 -200 0 0 {name=D6
model=diodevss_2kv
spiceprefix=X
m=1
}
C {sg13g2_pr/diodevdd_2kv.sym} 940 100 0 0 {name=D7
model=diodevdd_2kv
m=1
spiceprefix=X
}
C {sg13g2_pr/diodevss_2kv.sym} 940 190 0 0 {name=D8
model=diodevss_2kv
spiceprefix=X
m=1
}
C {sg13g2_pr/npn13G2.sym} 700 -190 0 0 {name=Q9
model=npn13G2
spiceprefix=X
Nx=10}
C {sg13g2_pr/npn13G2.sym} 700 0 0 0 {name=Q10
model=npn13G2
spiceprefix=X
Nx=10}
C {sg13g2_pr/npn13G2.sym} 800 -190 0 0 {name=Q11
model=npn13G2
spiceprefix=X
Nx=10}
C {sg13g2_pr/npn13G2.sym} 790 0 0 0 {name=Q12
model=npn13G2
spiceprefix=X
Nx=10}
C {iopin.sym} -490 -370 0 1 {name=p1 lab=VDD}
C {ipin.sym} -440 0 0 0 {name=p2 lab=IN}
C {opin.sym} 1080 -240 0 0 {name=p5 lab=OUT}
C {iopin.sym} 1090 150 0 0 {name=p3 lab=VSS}
C {ind.sym} 270 -310 0 1 {name=L1
m=1
value=26.8n
footprint=1206
device=inductor}
C {ind.sym} 270 90 0 1 {name=L2
m=1
value=2.36n
footprint=1206
device=inductor}
C {ind.sym} 160 0 3 1 {name=L3
m=1
value=39n
footprint=1206
device=inductor}
C {sg13g2_pr/rppd.sym} 70 930 0 0 {name=R4
w=0.5e-6
l=3.6e-6
model=rppd
spiceprefix=X
b=0
m=1
}
C {sg13g2_pr/rppd.sym} -20 730 0 0 {name=R5
w=0.5e-6
l=1.8e-6
model=rppd
spiceprefix=X
b=0
m=1
}
C {sg13g2_pr/rsil.sym} -150 1030 3 0 {name=R6
w=0.5e-6
l=2.4e-6
model=rsil
spiceprefix=X
b=0
m=1
}
C {sg13g2_pr/cap_rfcmim.sym} -10 1030 3 0 {name=C3 
model=rfcmim
w=60.0e-6
l=55.0e-6
wfeed=5.0e-6
spiceprefix=X}
C {sg13g2_pr/cap_rfcmim.sym} -10 1120 3 0 {name=C4 
model=rfcmim
w=60.0e-6
l=55.0e-6
wfeed=5.0e-6
spiceprefix=X}
C {sg13g2_pr/sg13_lv_rf_nmos.sym} 0 840 2 0 {name=M1
l=0.36u
w=10.0u
ng=5
m=1
rfmode=1
model=rfnmos
spiceprefix=X
}
C {sg13g2_pr/bondpad.sym} -420 620 0 0 {name=X5
model=bondpad
spiceprefix=X
size=100u
shape=0
padtype=0
}
C {sg13g2_pr/bondpad.sym} 1010 750 0 0 {name=X6
model=bondpad
spiceprefix=X
size=100u
shape=0
padtype=0
}
C {sg13g2_pr/bondpad.sym} 1020 1140 0 0 {name=X7
model=bondpad
spiceprefix=X
size=100u
shape=0
padtype=0
}
C {sg13g2_pr/diodevdd_2kv.sym} -260 620 0 0 {name=D9
model=diodevdd_2kv
m=1
spiceprefix=X
}
C {sg13g2_pr/diodevss_2kv.sym} -260 710 0 0 {name=D10
model=diodevss_2kv
spiceprefix=X
m=1
}
C {sg13g2_pr/bondpad.sym} -400 990 0 0 {name=X8
model=bondpad
spiceprefix=X
size=100u
shape=0
padtype=0
}
C {sg13g2_pr/diodevdd_2kv.sym} -270 980 0 0 {name=D11
model=diodevdd_2kv
m=1
spiceprefix=X
}
C {sg13g2_pr/diodevss_2kv.sym} -270 1070 0 0 {name=D12
model=diodevss_2kv
spiceprefix=X
m=1
}
C {sg13g2_pr/diodevdd_2kv.sym} 920 740 0 0 {name=D13
model=diodevdd_2kv
m=1
spiceprefix=X
}
C {sg13g2_pr/diodevss_2kv.sym} 920 830 0 0 {name=D14
model=diodevss_2kv
spiceprefix=X
m=1
}
C {sg13g2_pr/diodevdd_2kv.sym} 920 1130 0 0 {name=D15
model=diodevdd_2kv
m=1
spiceprefix=X
}
C {sg13g2_pr/diodevss_2kv.sym} 920 1220 0 0 {name=D16
model=diodevss_2kv
spiceprefix=X
m=1
}
C {sg13g2_pr/bondpad.sym} 520 1340 0 0 {name=X9
model=bondpad
spiceprefix=X
size=100u
shape=0
padtype=0
}
C {sg13g2_pr/diodevdd_2kv.sym} 430 1330 0 0 {name=D17
model=diodevdd_2kv
m=1
spiceprefix=X
}
C {sg13g2_pr/diodevss_2kv.sym} 430 1420 0 0 {name=D18
model=diodevss_2kv
spiceprefix=X
m=1
}
C {sg13g2_pr/bondpad.sym} 200 1360 0 0 {name=X10
model=bondpad
spiceprefix=X
size=100u
shape=0
padtype=0
}
C {sg13g2_pr/diodevdd_2kv.sym} 110 1350 0 0 {name=D19
model=diodevdd_2kv
m=1
spiceprefix=X
}
C {sg13g2_pr/diodevss_2kv.sym} 110 1440 0 0 {name=D20
model=diodevss_2kv
spiceprefix=X
m=1
}
C {sg13g2_pr/bondpad.sym} 0 1360 0 0 {name=X11
model=bondpad
spiceprefix=X
size=100u
shape=0
padtype=0
}
C {sg13g2_pr/diodevdd_2kv.sym} -90 1350 0 0 {name=D21
model=diodevdd_2kv
m=1
spiceprefix=X
}
C {sg13g2_pr/diodevss_2kv.sym} -90 1440 0 0 {name=D22
model=diodevss_2kv
spiceprefix=X
m=1
}
C {iopin.sym} -510 660 0 1 {name=p4 lab=VDD}
C {ipin.sym} -460 1030 0 0 {name=p6 lab=IN}
C {opin.sym} 1060 790 0 0 {name=p7 lab=OUT}
C {iopin.sym} 1070 1180 0 0 {name=p8 lab=VSS}
C {iopin.sym} 200 1400 0 0 {name=p9 lab=VBIAS_IN}
C {iopin.sym} 0 1400 0 0 {name=p10 lab=VBIAS_OUT}
C {iopin.sym} 520 1380 0 0 {name=p11 lab=IBIAS_IN}
C {sg13g2_pr/sg13_lv_rf_nmos.sym} 230 840 2 1 {name=M2
l=0.36u
w=200.0u
ng=200
m=1
rfmode=1
model=rfnmos
spiceprefix=X
}
C {sg13g2_pr/sg13_lv_rf_nmos.sym} 230 1030 2 1 {name=M4
l=0.36u
w=200.0u
ng=200
m=1
rfmode=1
model=rfnmos
spiceprefix=X
}
C {sg13g2_pr/rppd.sym} 40 2160 0 0 {name=R7
w=0.5e-6
l=3.6e-6
model=rppd
spiceprefix=X
b=0
m=1
}
C {sg13g2_pr/rppd.sym} -50 1960 0 0 {name=R8
w=0.5e-6
l=1.8e-6
model=rppd
spiceprefix=X
b=0
m=1
}
C {sg13g2_pr/rsil.sym} -180 2260 3 0 {name=R9
w=0.5e-6
l=2.4e-6
model=rsil
spiceprefix=X
b=0
m=1
}
C {sg13g2_pr/cap_rfcmim.sym} -40 2260 3 0 {name=C5 
model=rfcmim
w=60.0e-6
l=55.0e-6
wfeed=5.0e-6
spiceprefix=X}
C {sg13g2_pr/cap_rfcmim.sym} -40 2350 3 0 {name=C6 
model=rfcmim
w=60.0e-6
l=55.0e-6
wfeed=5.0e-6
spiceprefix=X}
C {sg13g2_pr/sg13_lv_rf_nmos.sym} -30 2070 2 0 {name=M5
l=0.36u
w=10.0u
ng=5
m=1
rfmode=1
model=rfnmos
spiceprefix=X
}
C {sg13g2_pr/bondpad.sym} -450 1850 0 0 {name=X12
model=bondpad
spiceprefix=X
size=100u
shape=0
padtype=0
}
C {sg13g2_pr/bondpad.sym} 980 1980 0 0 {name=X13
model=bondpad
spiceprefix=X
size=100u
shape=0
padtype=0
}
C {sg13g2_pr/bondpad.sym} 990 2370 0 0 {name=X14
model=bondpad
spiceprefix=X
size=100u
shape=0
padtype=0
}
C {sg13g2_pr/diodevdd_2kv.sym} -290 1850 0 0 {name=D23
model=diodevdd_2kv
m=1
spiceprefix=X
}
C {sg13g2_pr/diodevss_2kv.sym} -290 1940 0 0 {name=D24
model=diodevss_2kv
spiceprefix=X
m=1
}
C {sg13g2_pr/bondpad.sym} -430 2220 0 0 {name=X15
model=bondpad
spiceprefix=X
size=100u
shape=0
padtype=0
}
C {sg13g2_pr/npn13G2.sym} 200 2070 0 0 {name=Q13
model=npn13G2
spiceprefix=X
Nx=10
m=10}
C {sg13g2_pr/npn13G2.sym} 200 2260 0 0 {name=Q14
model=npn13G2
spiceprefix=X
Nx=10
m=10}
C {sg13g2_pr/npn13G2.sym} 320 2070 0 0 {name=Q15
model=npn13G2
spiceprefix=X
Nx=10}
C {sg13g2_pr/npn13G2.sym} 320 2260 0 0 {name=Q16
model=npn13G2
spiceprefix=X
Nx=10}
C {sg13g2_pr/npn13G2.sym} 440 2070 0 0 {name=Q17
model=npn13G2
spiceprefix=X
Nx=10}
C {sg13g2_pr/npn13G2.sym} 440 2260 0 0 {name=Q18
model=npn13G2
spiceprefix=X
Nx=10}
C {sg13g2_pr/npn13G2.sym} 550 2070 0 0 {name=Q19
model=npn13G2
spiceprefix=X
Nx=10}
C {sg13g2_pr/npn13G2.sym} 550 2260 0 0 {name=Q20
model=npn13G2
spiceprefix=X
Nx=10}
C {sg13g2_pr/diodevdd_2kv.sym} -300 2210 0 0 {name=D25
model=diodevdd_2kv
m=1
spiceprefix=X
}
C {sg13g2_pr/diodevss_2kv.sym} -300 2300 0 0 {name=D26
model=diodevss_2kv
spiceprefix=X
m=1
}
C {sg13g2_pr/diodevdd_2kv.sym} 890 1970 0 0 {name=D27
model=diodevdd_2kv
m=1
spiceprefix=X
}
C {sg13g2_pr/diodevss_2kv.sym} 890 2060 0 0 {name=D28
model=diodevss_2kv
spiceprefix=X
m=1
}
C {sg13g2_pr/diodevdd_2kv.sym} 890 2360 0 0 {name=D29
model=diodevdd_2kv
m=1
spiceprefix=X
}
C {sg13g2_pr/diodevss_2kv.sym} 890 2450 0 0 {name=D30
model=diodevss_2kv
spiceprefix=X
m=1
}
C {sg13g2_pr/npn13G2.sym} 650 2070 0 0 {name=Q21
model=npn13G2
spiceprefix=X
Nx=10}
C {sg13g2_pr/npn13G2.sym} 650 2260 0 0 {name=Q22
model=npn13G2
spiceprefix=X
Nx=10}
C {sg13g2_pr/npn13G2.sym} 750 2070 0 0 {name=Q23
model=npn13G2
spiceprefix=X
Nx=10}
C {sg13g2_pr/npn13G2.sym} 740 2260 0 0 {name=Q24
model=npn13G2
spiceprefix=X
Nx=10}
C {sg13g2_pr/bondpad.sym} 490 2570 0 0 {name=X16
model=bondpad
spiceprefix=X
size=100u
shape=0
padtype=0
}
C {sg13g2_pr/diodevdd_2kv.sym} 400 2560 0 0 {name=D31
model=diodevdd_2kv
m=1
spiceprefix=X
}
C {sg13g2_pr/diodevss_2kv.sym} 400 2650 0 0 {name=D32
model=diodevss_2kv
spiceprefix=X
m=1
}
C {sg13g2_pr/bondpad.sym} 170 2590 0 0 {name=X17
model=bondpad
spiceprefix=X
size=100u
shape=0
padtype=0
}
C {sg13g2_pr/diodevdd_2kv.sym} 80 2580 0 0 {name=D33
model=diodevdd_2kv
m=1
spiceprefix=X
}
C {sg13g2_pr/diodevss_2kv.sym} 80 2670 0 0 {name=D34
model=diodevss_2kv
spiceprefix=X
m=1
}
C {sg13g2_pr/bondpad.sym} -30 2590 0 0 {name=X18
model=bondpad
spiceprefix=X
size=100u
shape=0
padtype=0
}
C {sg13g2_pr/diodevdd_2kv.sym} -120 2580 0 0 {name=D35
model=diodevdd_2kv
m=1
spiceprefix=X
}
C {sg13g2_pr/diodevss_2kv.sym} -120 2670 0 0 {name=D36
model=diodevss_2kv
spiceprefix=X
m=1
}
C {iopin.sym} -540 1890 0 1 {name=p12 lab=VDD}
C {ipin.sym} -490 2260 0 0 {name=p13 lab=IN}
C {opin.sym} 1030 2020 0 0 {name=p14 lab=OUT}
C {iopin.sym} 1040 2410 0 0 {name=p15 lab=VSS}
C {iopin.sym} 170 2630 0 0 {name=p16 lab=VBAIS_IN}
C {iopin.sym} -30 2630 0 0 {name=p17 lab=VBIAS_OUT}
C {iopin.sym} 490 2610 0 0 {name=p18 lab=IBIAS_IN}
